VERSION 5.7 ;
  NOWIREEXTENSIONATPIN ON ;
  DIVIDERCHAR "/" ;
  BUSBITCHARS "[]" ;
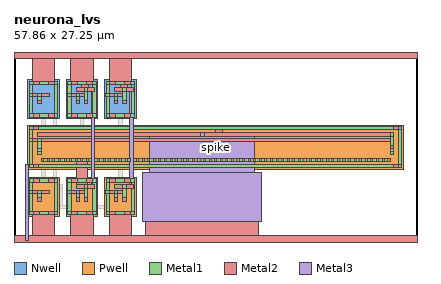
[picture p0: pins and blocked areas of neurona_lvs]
MACRO neurona_lvs
  CLASS BLOCK ;
  FOREIGN neurona_lvs ;
  ORIGIN 2.000 3.700 ;
  SIZE 57.860 BY 27.250 ;
  PIN spike
    ANTENNAGATEAREA 62.500000 ;
    ANTENNADIFFAREA 82.209595 ;
    PORT
      LAYER Nwell ;
        RECT 0.000 13.950 4.500 19.550 ;
        RECT 5.500 13.950 10.000 19.550 ;
        RECT 11.000 13.950 15.500 19.550 ;
      LAYER Pwell ;
        RECT 0.000 6.725 53.860 13.075 ;
        RECT 0.000 0.000 4.500 5.600 ;
        RECT 5.500 0.000 10.000 5.600 ;
        RECT 11.000 0.000 15.500 5.600 ;
      LAYER Metal1 ;
        RECT 0.230 18.840 0.730 19.340 ;
        RECT 1.600 18.840 2.900 19.340 ;
        RECT 3.770 18.840 4.270 19.340 ;
        RECT 0.230 17.645 0.690 18.840 ;
        RECT 0.190 17.145 0.690 17.645 ;
        RECT 1.400 17.145 1.900 17.645 ;
        RECT 0.230 14.660 0.690 17.145 ;
        RECT 1.420 16.595 1.880 17.145 ;
        RECT 1.400 16.095 1.900 16.595 ;
        RECT 3.810 14.660 4.270 18.840 ;
        RECT 5.730 18.840 6.230 19.340 ;
        RECT 7.100 18.840 8.400 19.340 ;
        RECT 9.270 18.840 9.770 19.340 ;
        RECT 5.730 17.645 6.190 18.840 ;
        RECT 8.100 17.945 8.600 18.445 ;
        RECT 5.690 17.145 6.190 17.645 ;
        RECT 6.900 17.145 7.400 17.645 ;
        RECT 0.230 14.160 0.730 14.660 ;
        RECT 1.600 14.160 2.900 14.660 ;
        RECT 3.770 14.160 4.270 14.660 ;
        RECT 5.730 14.660 6.190 17.145 ;
        RECT 6.920 16.595 7.380 17.145 ;
        RECT 8.120 16.595 8.580 17.945 ;
        RECT 6.900 16.095 7.400 16.595 ;
        RECT 8.100 16.095 8.600 16.595 ;
        RECT 9.310 14.660 9.770 18.840 ;
        RECT 11.230 18.840 11.730 19.340 ;
        RECT 12.600 18.840 13.900 19.340 ;
        RECT 14.770 18.840 15.270 19.340 ;
        RECT 11.230 17.645 11.690 18.840 ;
        RECT 13.600 17.945 14.100 18.445 ;
        RECT 11.190 17.145 11.690 17.645 ;
        RECT 12.400 17.145 12.900 17.645 ;
        RECT 5.730 14.160 6.230 14.660 ;
        RECT 7.100 14.160 8.400 14.660 ;
        RECT 9.270 14.160 9.770 14.660 ;
        RECT 11.230 14.660 11.690 17.145 ;
        RECT 12.420 16.595 12.880 17.145 ;
        RECT 13.620 16.595 14.080 17.945 ;
        RECT 12.400 16.095 12.900 16.595 ;
        RECT 13.600 16.095 14.100 16.595 ;
        RECT 14.810 14.660 15.270 18.840 ;
        RECT 11.230 14.160 11.730 14.660 ;
        RECT 12.600 14.160 13.900 14.660 ;
        RECT 14.770 14.160 15.270 14.660 ;
        RECT 0.230 12.365 0.730 12.865 ;
        RECT 1.480 12.365 52.380 12.865 ;
        RECT 53.130 12.365 53.630 12.865 ;
        RECT 0.230 11.175 0.690 12.365 ;
        RECT 51.960 11.475 52.460 11.975 ;
        RECT 0.190 10.675 0.690 11.175 ;
        RECT 1.400 10.675 1.900 11.175 ;
        RECT 0.230 7.435 0.690 10.675 ;
        RECT 1.420 9.750 1.880 10.675 ;
        RECT 51.980 9.750 52.440 11.475 ;
        RECT 1.400 9.250 1.900 9.750 ;
        RECT 51.960 9.250 52.460 9.750 ;
        RECT 1.420 8.875 1.880 9.250 ;
        RECT 51.980 8.875 52.440 9.250 ;
        RECT 2.280 7.830 2.780 8.330 ;
        RECT 3.080 7.830 3.580 8.330 ;
        RECT 3.880 7.830 4.380 8.330 ;
        RECT 4.680 7.830 5.180 8.330 ;
        RECT 5.480 7.830 5.980 8.330 ;
        RECT 6.280 7.830 6.780 8.330 ;
        RECT 7.080 7.830 7.580 8.330 ;
        RECT 7.880 7.830 8.380 8.330 ;
        RECT 8.680 7.830 9.180 8.330 ;
        RECT 9.480 7.830 9.980 8.330 ;
        RECT 10.280 7.830 10.780 8.330 ;
        RECT 11.080 7.830 11.580 8.330 ;
        RECT 11.880 7.830 12.380 8.330 ;
        RECT 12.680 7.830 13.180 8.330 ;
        RECT 13.480 7.830 13.980 8.330 ;
        RECT 14.280 7.830 14.780 8.330 ;
        RECT 15.080 7.830 15.580 8.330 ;
        RECT 15.880 7.830 16.380 8.330 ;
        RECT 16.680 7.830 17.180 8.330 ;
        RECT 17.480 7.830 17.980 8.330 ;
        RECT 18.280 7.830 18.780 8.330 ;
        RECT 19.080 7.830 19.580 8.330 ;
        RECT 19.880 7.830 20.380 8.330 ;
        RECT 20.680 7.830 21.180 8.330 ;
        RECT 21.480 7.830 21.980 8.330 ;
        RECT 22.280 7.830 22.780 8.330 ;
        RECT 23.080 7.830 23.580 8.330 ;
        RECT 23.880 7.830 24.380 8.330 ;
        RECT 24.680 7.830 25.180 8.330 ;
        RECT 25.480 7.830 25.980 8.330 ;
        RECT 26.280 7.830 26.780 8.330 ;
        RECT 27.080 7.830 27.580 8.330 ;
        RECT 27.880 7.830 28.380 8.330 ;
        RECT 28.680 7.830 29.180 8.330 ;
        RECT 29.480 7.830 29.980 8.330 ;
        RECT 30.280 7.830 30.780 8.330 ;
        RECT 31.080 7.830 31.580 8.330 ;
        RECT 31.880 7.830 32.380 8.330 ;
        RECT 32.680 7.830 33.180 8.330 ;
        RECT 33.480 7.830 33.980 8.330 ;
        RECT 34.280 7.830 34.780 8.330 ;
        RECT 35.080 7.830 35.580 8.330 ;
        RECT 35.880 7.830 36.380 8.330 ;
        RECT 36.680 7.830 37.180 8.330 ;
        RECT 37.480 7.830 37.980 8.330 ;
        RECT 38.280 7.830 38.780 8.330 ;
        RECT 39.080 7.830 39.580 8.330 ;
        RECT 39.880 7.830 40.380 8.330 ;
        RECT 40.680 7.830 41.180 8.330 ;
        RECT 41.480 7.830 41.980 8.330 ;
        RECT 42.280 7.830 42.780 8.330 ;
        RECT 43.080 7.830 43.580 8.330 ;
        RECT 43.880 7.830 44.380 8.330 ;
        RECT 44.680 7.830 45.180 8.330 ;
        RECT 45.480 7.830 45.980 8.330 ;
        RECT 46.280 7.830 46.780 8.330 ;
        RECT 47.080 7.830 47.580 8.330 ;
        RECT 47.880 7.830 48.380 8.330 ;
        RECT 48.680 7.830 49.180 8.330 ;
        RECT 49.480 7.830 49.980 8.330 ;
        RECT 50.280 7.830 50.780 8.330 ;
        RECT 51.080 7.830 51.580 8.330 ;
        RECT 53.170 7.435 53.630 12.365 ;
        RECT 0.230 6.935 0.730 7.435 ;
        RECT 1.480 6.935 52.380 7.435 ;
        RECT 53.130 6.935 53.630 7.435 ;
        RECT 0.230 4.890 0.730 5.390 ;
        RECT 1.600 4.890 2.900 5.390 ;
        RECT 3.770 4.890 4.270 5.390 ;
        RECT 0.230 3.695 0.690 4.890 ;
        RECT 0.190 3.195 0.690 3.695 ;
        RECT 1.400 3.195 1.900 3.695 ;
        RECT 0.230 0.710 0.690 3.195 ;
        RECT 1.420 2.645 1.880 3.195 ;
        RECT 1.400 2.145 1.900 2.645 ;
        RECT 3.810 0.710 4.270 4.890 ;
        RECT 5.730 4.890 6.230 5.390 ;
        RECT 7.100 4.890 8.400 5.390 ;
        RECT 9.270 4.890 9.770 5.390 ;
        RECT 5.730 3.695 6.190 4.890 ;
        RECT 8.100 3.995 8.600 4.495 ;
        RECT 5.690 3.195 6.190 3.695 ;
        RECT 6.900 3.195 7.400 3.695 ;
        RECT 0.230 0.210 0.730 0.710 ;
        RECT 1.600 0.210 2.900 0.710 ;
        RECT 3.770 0.210 4.270 0.710 ;
        RECT 5.730 0.710 6.190 3.195 ;
        RECT 6.920 2.645 7.380 3.195 ;
        RECT 8.120 2.645 8.580 3.995 ;
        RECT 6.900 2.145 7.400 2.645 ;
        RECT 8.100 2.145 8.600 2.645 ;
        RECT 9.310 0.710 9.770 4.890 ;
        RECT 11.230 4.890 11.730 5.390 ;
        RECT 12.600 4.890 13.900 5.390 ;
        RECT 14.770 4.890 15.270 5.390 ;
        RECT 11.230 3.695 11.690 4.890 ;
        RECT 13.600 3.995 14.100 4.495 ;
        RECT 11.190 3.195 11.690 3.695 ;
        RECT 12.400 3.195 12.900 3.695 ;
        RECT 5.730 0.210 6.230 0.710 ;
        RECT 7.100 0.210 8.400 0.710 ;
        RECT 9.270 0.210 9.770 0.710 ;
        RECT 11.230 0.710 11.690 3.195 ;
        RECT 12.420 2.645 12.880 3.195 ;
        RECT 13.620 2.645 14.080 3.995 ;
        RECT 12.400 2.145 12.900 2.645 ;
        RECT 13.600 2.145 14.100 2.645 ;
        RECT 14.810 0.710 15.270 4.890 ;
        RECT 11.230 0.210 11.730 0.710 ;
        RECT 12.600 0.210 13.900 0.710 ;
        RECT 14.770 0.210 15.270 0.710 ;
      LAYER Metal2 ;
        RECT -2.000 22.550 55.860 23.550 ;
        RECT 0.640 19.340 3.860 22.550 ;
        RECT 6.140 19.340 9.360 22.550 ;
        RECT 11.640 19.340 14.860 22.550 ;
        RECT 0.230 18.840 4.270 19.340 ;
        RECT 5.730 18.840 9.770 19.340 ;
        RECT 11.230 18.840 15.270 19.340 ;
        RECT 7.750 18.445 8.750 18.840 ;
        RECT 13.250 18.445 14.250 18.840 ;
        RECT 6.900 17.945 9.600 18.445 ;
        RECT 12.400 17.945 15.100 18.445 ;
        RECT 0.190 17.145 3.100 17.645 ;
        RECT 5.690 17.145 8.600 17.645 ;
        RECT 11.190 17.145 14.100 17.645 ;
        RECT 1.400 16.095 1.900 16.595 ;
        RECT 6.900 16.095 7.400 16.595 ;
        RECT 8.100 16.095 8.600 16.595 ;
        RECT 12.400 16.095 12.900 16.595 ;
        RECT 13.600 16.095 14.100 16.595 ;
        RECT 0.230 14.160 4.270 14.660 ;
        RECT 5.730 14.160 9.770 14.660 ;
        RECT 11.230 14.160 15.270 14.660 ;
        RECT 0.230 12.365 53.630 12.865 ;
        RECT 26.930 11.975 27.930 12.365 ;
        RECT 1.400 11.475 52.460 11.975 ;
        RECT 0.190 10.675 52.460 11.175 ;
        RECT 1.400 8.875 1.900 10.125 ;
        RECT 51.960 8.875 52.460 10.125 ;
        RECT 1.930 7.830 51.930 8.330 ;
        RECT 6.900 7.435 8.600 7.830 ;
        RECT -0.360 6.935 53.630 7.435 ;
        RECT 6.900 5.390 8.600 6.935 ;
        RECT 0.230 4.890 4.270 5.390 ;
        RECT 5.730 4.890 9.770 5.390 ;
        RECT 11.230 4.890 15.270 5.390 ;
        RECT 6.900 4.495 8.600 4.890 ;
        RECT 6.900 3.995 9.600 4.495 ;
        RECT 12.400 3.995 15.100 4.495 ;
        RECT 0.190 3.195 3.100 3.695 ;
        RECT 5.690 3.195 8.600 3.695 ;
        RECT 11.190 3.195 14.100 3.695 ;
        RECT 1.400 2.145 1.900 2.645 ;
        RECT 6.900 2.145 7.400 2.645 ;
        RECT 8.100 2.145 8.600 2.645 ;
        RECT 12.400 2.145 12.900 2.645 ;
        RECT 13.600 2.145 14.100 2.645 ;
        RECT 0.230 0.210 4.270 0.710 ;
        RECT 5.730 0.210 9.770 0.710 ;
        RECT 11.230 0.210 15.270 0.710 ;
        RECT 0.640 -2.700 3.860 0.210 ;
        RECT 6.140 -2.700 9.360 0.210 ;
        RECT 11.640 -2.700 14.860 0.210 ;
        RECT 16.500 -0.700 33.500 6.300 ;
        RECT 16.900 -2.700 33.100 -0.700 ;
        RECT -2.000 -3.700 55.860 -2.700 ;
      LAYER Metal3 ;
        RECT -0.360 -3.450 0.140 7.435 ;
        RECT 9.100 3.995 9.600 18.445 ;
        RECT 14.600 3.995 15.100 18.445 ;
        RECT 24.750 11.475 25.250 11.975 ;
        RECT 17.500 6.300 32.500 11.475 ;
        RECT 16.500 -0.700 33.500 6.300 ;
    END
  END spike
  OBS
      LAYER Metal1 ;
        RECT 2.600 17.945 3.100 18.445 ;
        RECT 2.620 16.595 3.080 17.945 ;
        RECT 2.600 16.095 3.100 16.595 ;
        RECT 2.000 15.055 2.500 15.555 ;
        RECT 7.500 15.055 8.000 15.555 ;
        RECT 13.000 15.055 13.500 15.555 ;
        RECT 2.600 3.995 3.100 4.495 ;
        RECT 2.620 2.645 3.080 3.995 ;
        RECT 2.600 2.145 3.100 2.645 ;
        RECT 2.000 1.105 2.500 1.605 ;
        RECT 7.500 1.105 8.000 1.605 ;
        RECT 13.000 1.105 13.500 1.605 ;
      LAYER Metal2 ;
        RECT 1.400 17.945 4.100 18.445 ;
        RECT 2.600 16.095 3.100 16.595 ;
        RECT 2.000 15.555 2.500 15.805 ;
        RECT 7.500 15.555 8.000 15.805 ;
        RECT 13.000 15.555 13.500 15.805 ;
        RECT 1.930 15.055 2.570 15.555 ;
        RECT 7.430 15.055 8.070 15.555 ;
        RECT 12.930 15.055 13.570 15.555 ;
        RECT 1.400 3.995 4.950 4.495 ;
        RECT 2.600 2.145 3.100 2.645 ;
        RECT 1.930 1.105 2.570 1.855 ;
        RECT 4.450 1.605 4.950 3.995 ;
        RECT 7.430 1.605 8.070 1.855 ;
        RECT 12.930 1.605 13.570 1.855 ;
        RECT 4.450 1.105 13.570 1.605 ;
      LAYER Metal3 ;
        RECT 2.000 1.355 2.500 15.805 ;
        RECT 3.600 3.995 4.100 18.445 ;
        RECT 4.450 3.995 4.950 4.495 ;
        RECT 7.500 1.355 8.000 15.805 ;
        RECT 13.000 1.355 13.500 15.805 ;
  END
END neurona_lvs
END LIBRARY

